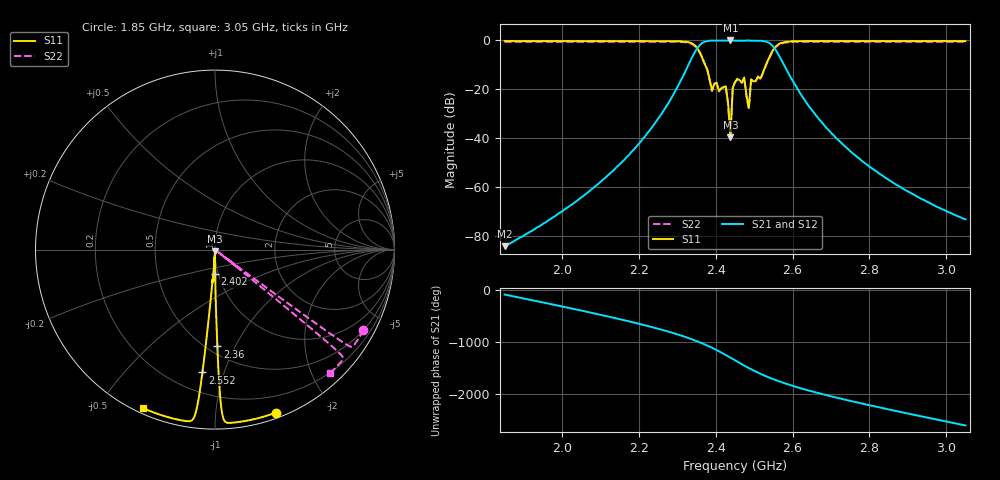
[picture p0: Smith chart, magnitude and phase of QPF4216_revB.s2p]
! written by passband
# GHZ S DB R 50
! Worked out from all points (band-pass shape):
!   201 points, 1.85 GHz to 3.05 GHz, reference 50 ohm
!   highest |S21| = 0.00 dB at 2.438 GHz (marker M1); lowest = -84.3 dB at 1.85 GHz (marker M2)
!   |S21| within 3 dB of the highest: 2.353 GHz to 2.552 GHz (199.1 MHz wide, 8.12 % of centre)
!   lowest |S11| = -39.7 dB at 2.438 GHz (marker M3), VSWR 1.02, Z = 50 - j1.04 ohm
!   |S11| at or under -10 dB: 2.372 GHz to 2.531 GHz (158.5 MHz wide, 6.47 % of centre)
!   |S22| runs from -39.9 to -0.5 dB; largest |S21 - S12| = 0
!   S11 on the Smith chart (normalised r, x): 1.85 GHz: 0.05, -1.44; 2.36 GHz: 0.56, -0.85; 2.402 GHz: 0.96, -0.27; 2.552 GHz: 0.33, -0.85; 3.05 GHz: 0.02, -0.64
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1.85  -0.27 -69.5  -84.35 -80.7  -84.35 -80.7  -0.53 -28.5
2.054  -0.27 -77.1  -63.91 -37.0  -63.91 -37.0  -0.53 -31.7
2.252  -0.27 -84.6  -31.58 -24.8  -31.58 -24.8  -0.54 -34.7
2.336  -1.10 -87.7  -7.59 141.1  -7.59 141.1  -1.36 -36.0
2.36  -5.36 -88.6  -1.61 72.2  -1.61 72.2  -5.62 -36.4
2.384  -16.05 -89.5  -0.12 -5.9  -0.12 -5.9  -16.31 -36.7
2.402  -17.27 -90.2  -0.09 -71.3  -0.09 -71.3  -17.54 -37.0
2.414  -19.58 -90.7  -0.05 -118.1  -0.05 -118.1  -19.85 -37.2
2.426  -18.83 -91.1  -0.06 -167.2  -0.06 -167.2  -19.09 -37.4
2.438  -39.66 -91.6  -0.00 142.1  -0.00 142.1  -39.93 -37.6
2.444  -19.57 -91.8  -0.05 116.4  -0.05 116.4  -19.83 -37.7
2.45  -17.02 -92.0  -0.09 90.6  -0.09 90.6  -17.29 -37.8
2.468  -17.24 -92.7  -0.09 14.0  -0.09 14.0  -17.50 -38.0
2.486  -27.69 -93.4  -0.01 -59.3  -0.01 -59.3  -27.95 -38.3
2.492  -15.91 -93.6  -0.12 -82.6  -0.12 -82.6  -16.17 -38.4
2.516  -15.68 -94.5  -0.13 -169.3  -0.13 -169.3  -15.95 -38.8
2.534  -8.80 -95.2  -0.66 132.5  -0.66 132.5  -9.07 -39.0
2.552  -3.25 -95.8  -3.04 79.6  -3.04 79.6  -3.51 -39.3
2.588  -0.49 -97.2  -13.10 -13.7  -13.10 -13.7  -0.75 -39.9
2.654  -0.27 -99.7  -29.35 -156.5  -29.35 -156.5  -0.54 -40.9
2.852  -0.27 -107.1  -57.36 -140.3  -57.36 -140.3  -0.53 -43.9
3.05  -0.27 -114.5  -73.34 -86.4  -73.34 -86.4  -0.53 -47.0
